###############################################################
#  Generated by:      Cadence Innovus 21.35-s114_1
#  OS:                Linux x86_64(Host ID pc231.ee.hacettepe.edu.tr)
#  Generated on:      Wed Dec 24 15:13:07 2025
#  Design:            adc_subsystem_macro
#  Command:           write_lef_abstract -5.7 outputs/adc_subsystem_macro/adc_subsystem_macro.lef
###############################################################

VERSION 5.7 ;

BUSBITCHARS "[]" ;
DIVIDERCHAR "/" ;

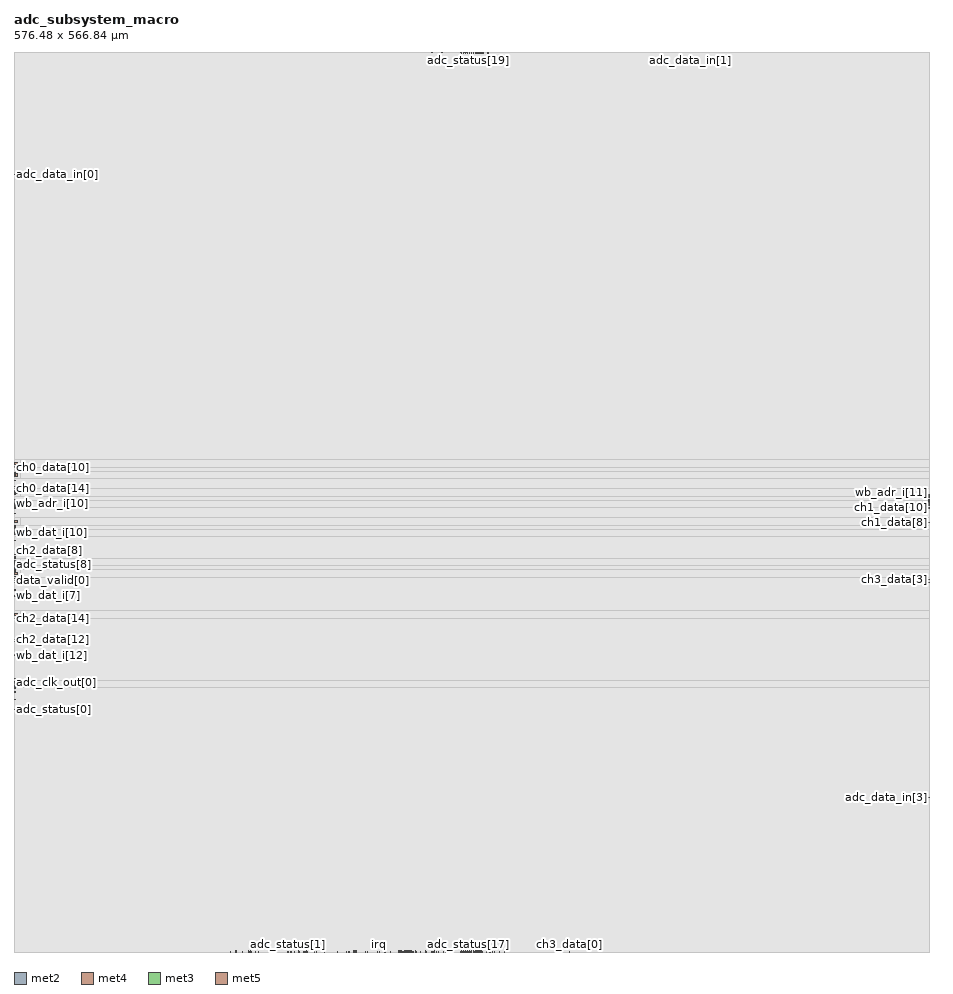
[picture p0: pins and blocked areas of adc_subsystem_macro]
MACRO adc_subsystem_macro
  CLASS BLOCK ;
  SIZE 576.480000 BY 566.840000 ;
  FOREIGN adc_subsystem_macro 0.000000 0.000000 ;
  ORIGIN 0 0 ;
  SYMMETRY X Y R90 ;
  PIN clk
    DIRECTION INPUT ;
    USE SIGNAL ;
    PORT
      LAYER met2 ;
        RECT 276.170000 0.000000 276.310000 0.485000 ;
    END
  END clk
  PIN rst_n
    DIRECTION INPUT ;
    USE SIGNAL ;
    PORT
      LAYER met4 ;
        RECT 275.610000 0.000000 275.910000 0.800000 ;
    END
  END rst_n
  PIN wb_adr_i[31]
    DIRECTION INPUT ;
    USE SIGNAL ;
    PORT
      LAYER met4 ;
        RECT 291.600000 0.000000 291.900000 0.800000 ;
    END
  END wb_adr_i[31]
  PIN wb_adr_i[30]
    DIRECTION INPUT ;
    USE SIGNAL ;
    PORT
      LAYER met2 ;
        RECT 284.330000 566.355000 284.470000 566.840000 ;
    END
  END wb_adr_i[30]
  PIN wb_adr_i[29]
    DIRECTION INPUT ;
    USE SIGNAL ;
    PORT
      LAYER met2 ;
        RECT 292.010000 0.000000 292.150000 0.485000 ;
    END
  END wb_adr_i[29]
  PIN wb_adr_i[28]
    DIRECTION INPUT ;
    USE SIGNAL ;
    PORT
      LAYER met4 ;
        RECT 284.220000 566.040000 284.520000 566.840000 ;
    END
  END wb_adr_i[28]
  PIN wb_adr_i[27]
    DIRECTION INPUT ;
    USE SIGNAL ;
    PORT
      LAYER met2 ;
        RECT 292.970000 566.355000 293.110000 566.840000 ;
    END
  END wb_adr_i[27]
  PIN wb_adr_i[26]
    DIRECTION INPUT ;
    USE SIGNAL ;
    PORT
      LAYER met4 ;
        RECT 292.830000 566.040000 293.130000 566.840000 ;
    END
  END wb_adr_i[26]
  PIN wb_adr_i[25]
    DIRECTION INPUT ;
    USE SIGNAL ;
    PORT
      LAYER met2 ;
        RECT 292.970000 0.000000 293.110000 0.485000 ;
    END
  END wb_adr_i[25]
  PIN wb_adr_i[24]
    DIRECTION INPUT ;
    USE SIGNAL ;
    PORT
      LAYER met4 ;
        RECT 292.830000 0.000000 293.130000 0.800000 ;
    END
  END wb_adr_i[24]
  PIN wb_adr_i[23]
    DIRECTION INPUT ;
    USE SIGNAL ;
    PORT
      LAYER met2 ;
        RECT 283.370000 566.355000 283.510000 566.840000 ;
    END
  END wb_adr_i[23]
  PIN wb_adr_i[22]
    DIRECTION INPUT ;
    USE SIGNAL ;
    PORT
      LAYER met3 ;
        RECT 0.000000 283.260000 0.800000 283.560000 ;
    END
  END wb_adr_i[22]
  PIN wb_adr_i[21]
    DIRECTION INPUT ;
    USE SIGNAL ;
    PORT
      LAYER met3 ;
        RECT 575.680000 283.260000 576.480000 283.560000 ;
    END
  END wb_adr_i[21]
  PIN wb_adr_i[20]
    DIRECTION INPUT ;
    USE SIGNAL ;
    PORT
      LAYER met4 ;
        RECT 282.990000 566.040000 283.290000 566.840000 ;
    END
  END wb_adr_i[20]
  PIN wb_adr_i[19]
    DIRECTION INPUT ;
    USE SIGNAL ;
    PORT
      LAYER met4 ;
        RECT 282.990000 0.000000 283.290000 0.800000 ;
    END
  END wb_adr_i[19]
  PIN wb_adr_i[18]
    DIRECTION INPUT ;
    USE SIGNAL ;
    PORT
      LAYER met2 ;
        RECT 282.410000 566.355000 282.550000 566.840000 ;
    END
  END wb_adr_i[18]
  PIN wb_adr_i[17]
    DIRECTION INPUT ;
    USE SIGNAL ;
    PORT
      LAYER met2 ;
        RECT 293.930000 566.355000 294.070000 566.840000 ;
    END
  END wb_adr_i[17]
  PIN wb_adr_i[16]
    DIRECTION INPUT ;
    USE SIGNAL ;
    PORT
      LAYER met2 ;
        RECT 282.410000 0.000000 282.550000 0.485000 ;
    END
  END wb_adr_i[16]
  PIN wb_adr_i[15]
    DIRECTION INPUT ;
    USE SIGNAL ;
    PORT
      LAYER met2 ;
        RECT 293.930000 0.000000 294.070000 0.485000 ;
    END
  END wb_adr_i[15]
  PIN wb_adr_i[14]
    DIRECTION INPUT ;
    USE SIGNAL ;
    PORT
      LAYER met4 ;
        RECT 294.060000 566.040000 294.360000 566.840000 ;
    END
  END wb_adr_i[14]
  PIN wb_adr_i[13]
    DIRECTION INPUT ;
    USE SIGNAL ;
    PORT
      LAYER met4 ;
        RECT 294.060000 0.000000 294.360000 0.800000 ;
    END
  END wb_adr_i[13]
  PIN wb_adr_i[12]
    DIRECTION INPUT ;
    USE SIGNAL ;
    PORT
      LAYER met3 ;
        RECT 0.000000 284.480000 0.800000 284.780000 ;
    END
  END wb_adr_i[12]
  PIN wb_adr_i[11]
    DIRECTION INPUT ;
    USE SIGNAL ;
    PORT
      LAYER met3 ;
        RECT 575.680000 284.480000 576.480000 284.780000 ;
    END
  END wb_adr_i[11]
  PIN wb_adr_i[10]
    DIRECTION INPUT ;
    USE SIGNAL ;
    PORT
      LAYER met3 ;
        RECT 0.000000 282.040000 0.800000 282.340000 ;
    END
  END wb_adr_i[10]
  PIN wb_adr_i[9]
    DIRECTION INPUT ;
    USE SIGNAL ;
    PORT
      LAYER met5 ;
        RECT 0.000000 281.390000 2.500000 282.990000 ;
    END
  END wb_adr_i[9]
  PIN wb_adr_i[8]
    DIRECTION INPUT ;
    USE SIGNAL ;
    PORT
      LAYER met3 ;
        RECT 575.680000 282.040000 576.480000 282.340000 ;
    END
  END wb_adr_i[8]
  PIN wb_adr_i[7]
    DIRECTION INPUT ;
    USE SIGNAL ;
    PORT
      LAYER met2 ;
        RECT 259.370000 0.000000 259.510000 0.485000 ;
    END
  END wb_adr_i[7]
  PIN wb_adr_i[6]
    DIRECTION INPUT ;
    USE SIGNAL ;
    PORT
      LAYER met4 ;
        RECT 259.005000 0.000000 259.305000 0.800000 ;
    END
  END wb_adr_i[6]
  PIN wb_adr_i[5]
    DIRECTION INPUT ;
    USE SIGNAL ;
    PORT
      LAYER met2 ;
        RECT 233.930000 0.000000 234.070000 0.485000 ;
    END
  END wb_adr_i[5]
  PIN wb_adr_i[4]
    DIRECTION INPUT ;
    USE SIGNAL ;
    PORT
      LAYER met4 ;
        RECT 248.550000 0.000000 248.850000 0.800000 ;
    END
  END wb_adr_i[4]
  PIN wb_adr_i[3]
    DIRECTION INPUT ;
    USE SIGNAL ;
    PORT
      LAYER met2 ;
        RECT 244.010000 0.000000 244.150000 0.485000 ;
    END
  END wb_adr_i[3]
  PIN wb_adr_i[2]
    DIRECTION INPUT ;
    USE SIGNAL ;
    PORT
      LAYER met2 ;
        RECT 248.330000 0.000000 248.470000 0.485000 ;
    END
  END wb_adr_i[2]
  PIN wb_adr_i[1]
    DIRECTION INPUT ;
    USE SIGNAL ;
    PORT
      LAYER met5 ;
        RECT 573.980000 281.390000 576.480000 282.990000 ;
    END
  END wb_adr_i[1]
  PIN wb_adr_i[0]
    DIRECTION INPUT ;
    USE SIGNAL ;
    PORT
      LAYER met4 ;
        RECT 281.760000 566.040000 282.060000 566.840000 ;
    END
  END wb_adr_i[0]
  PIN wb_dat_o[31]
    DIRECTION OUTPUT ;
    USE SIGNAL ;
    PORT
      LAYER met2 ;
        RECT 250.250000 0.000000 250.390000 0.485000 ;
    END
  END wb_dat_o[31]
  PIN wb_dat_o[30]
    DIRECTION OUTPUT ;
    USE SIGNAL ;
    PORT
      LAYER met2 ;
        RECT 242.570000 0.000000 242.710000 0.485000 ;
    END
  END wb_dat_o[30]
  PIN wb_dat_o[29]
    DIRECTION OUTPUT ;
    USE SIGNAL ;
    PORT
      LAYER met2 ;
        RECT 174.410000 0.000000 174.550000 0.485000 ;
    END
  END wb_dat_o[29]
  PIN wb_dat_o[28]
    DIRECTION OUTPUT ;
    USE SIGNAL ;
    PORT
      LAYER met4 ;
        RECT 147.690000 0.000000 147.990000 0.800000 ;
    END
  END wb_dat_o[28]
  PIN wb_dat_o[27]
    DIRECTION OUTPUT ;
    USE SIGNAL ;
    PORT
      LAYER met4 ;
        RECT 246.090000 0.000000 246.390000 0.800000 ;
    END
  END wb_dat_o[27]
  PIN wb_dat_o[26]
    DIRECTION OUTPUT ;
    USE SIGNAL ;
    PORT
      LAYER met4 ;
        RECT 179.055000 0.000000 179.355000 0.800000 ;
    END
  END wb_dat_o[26]
  PIN wb_dat_o[25]
    DIRECTION OUTPUT ;
    USE SIGNAL ;
    PORT
      LAYER met2 ;
        RECT 136.490000 0.000000 136.630000 0.485000 ;
    END
  END wb_dat_o[25]
  PIN wb_dat_o[24]
    DIRECTION OUTPUT ;
    USE SIGNAL ;
    PORT
      LAYER met2 ;
        RECT 183.530000 0.000000 183.670000 0.485000 ;
    END
  END wb_dat_o[24]
  PIN wb_dat_o[23]
    DIRECTION OUTPUT ;
    USE SIGNAL ;
    PORT
      LAYER met2 ;
        RECT 244.970000 0.000000 245.110000 0.485000 ;
    END
  END wb_dat_o[23]
  PIN wb_dat_o[22]
    DIRECTION OUTPUT ;
    USE SIGNAL ;
    PORT
      LAYER met2 ;
        RECT 139.370000 0.000000 139.510000 0.485000 ;
    END
  END wb_dat_o[22]
  PIN wb_dat_o[21]
    DIRECTION OUTPUT ;
    USE SIGNAL ;
    PORT
      LAYER met4 ;
        RECT 247.320000 0.000000 247.620000 0.800000 ;
    END
  END wb_dat_o[21]
  PIN wb_dat_o[20]
    DIRECTION OUTPUT ;
    USE SIGNAL ;
    PORT
      LAYER met2 ;
        RECT 143.690000 0.000000 143.830000 0.485000 ;
    END
  END wb_dat_o[20]
  PIN wb_dat_o[19]
    DIRECTION OUTPUT ;
    USE SIGNAL ;
    PORT
      LAYER met2 ;
        RECT 209.450000 0.000000 209.590000 0.485000 ;
    END
  END wb_dat_o[19]
  PIN wb_dat_o[18]
    DIRECTION OUTPUT ;
    USE SIGNAL ;
    PORT
      LAYER met4 ;
        RECT 214.110000 0.000000 214.410000 0.800000 ;
    END
  END wb_dat_o[18]
  PIN wb_dat_o[17]
    DIRECTION OUTPUT ;
    USE SIGNAL ;
    PORT
      LAYER met2 ;
        RECT 182.570000 0.000000 182.710000 0.485000 ;
    END
  END wb_dat_o[17]
  PIN wb_dat_o[16]
    DIRECTION OUTPUT ;
    USE SIGNAL ;
    PORT
      LAYER met4 ;
        RECT 139.695000 0.000000 139.995000 0.800000 ;
    END
  END wb_dat_o[16]
  PIN wb_dat_o[15]
    DIRECTION OUTPUT ;
    USE SIGNAL ;
    PORT
      LAYER met3 ;
        RECT 0.000000 163.700000 0.800000 164.000000 ;
    END
  END wb_dat_o[15]
  PIN wb_dat_o[14]
    DIRECTION OUTPUT ;
    USE SIGNAL ;
    PORT
      LAYER met5 ;
        RECT 0.000000 211.850000 2.500000 213.450000 ;
    END
  END wb_dat_o[14]
  PIN wb_dat_o[13]
    DIRECTION OUTPUT ;
    USE SIGNAL ;
    PORT
      LAYER met5 ;
        RECT 0.000000 167.930000 2.500000 169.530000 ;
    END
  END wb_dat_o[13]
  PIN wb_dat_o[12]
    DIRECTION OUTPUT ;
    USE SIGNAL ;
    PORT
      LAYER met3 ;
        RECT 0.000000 195.420000 0.800000 195.720000 ;
    END
  END wb_dat_o[12]
  PIN wb_dat_o[11]
    DIRECTION OUTPUT ;
    USE SIGNAL ;
    PORT
      LAYER met3 ;
        RECT 0.000000 233.850000 0.800000 234.150000 ;
    END
  END wb_dat_o[11]
  PIN wb_dat_o[10]
    DIRECTION OUTPUT ;
    USE SIGNAL ;
    PORT
      LAYER met3 ;
        RECT 0.000000 249.100000 0.800000 249.400000 ;
    END
  END wb_dat_o[10]
  PIN wb_dat_o[9]
    DIRECTION OUTPUT ;
    USE SIGNAL ;
    PORT
      LAYER met3 ;
        RECT 0.000000 268.010000 0.800000 268.310000 ;
    END
  END wb_dat_o[9]
  PIN wb_dat_o[8]
    DIRECTION OUTPUT ;
    USE SIGNAL ;
    PORT
      LAYER met3 ;
        RECT 0.000000 250.320000 0.800000 250.620000 ;
    END
  END wb_dat_o[8]
  PIN wb_dat_o[7]
    DIRECTION OUTPUT ;
    USE SIGNAL ;
    PORT
      LAYER met3 ;
        RECT 0.000000 232.630000 0.800000 232.930000 ;
    END
  END wb_dat_o[7]
  PIN wb_dat_o[6]
    DIRECTION OUTPUT ;
    USE SIGNAL ;
    PORT
      LAYER met3 ;
        RECT 0.000000 275.940000 0.800000 276.240000 ;
    END
  END wb_dat_o[6]
  PIN wb_dat_o[5]
    DIRECTION OUTPUT ;
    USE SIGNAL ;
    PORT
      LAYER met3 ;
        RECT 0.000000 279.600000 0.800000 279.900000 ;
    END
  END wb_dat_o[5]
  PIN wb_dat_o[4]
    DIRECTION OUTPUT ;
    USE SIGNAL ;
    PORT
      LAYER met3 ;
        RECT 0.000000 280.820000 0.800000 281.120000 ;
    END
  END wb_dat_o[4]
  PIN wb_dat_o[3]
    DIRECTION OUTPUT ;
    USE SIGNAL ;
    PORT
      LAYER met2 ;
        RECT 221.450000 0.000000 221.590000 0.485000 ;
    END
  END wb_dat_o[3]
  PIN wb_dat_o[2]
    DIRECTION OUTPUT ;
    USE SIGNAL ;
    PORT
      LAYER met4 ;
        RECT 242.400000 0.000000 242.700000 0.800000 ;
    END
  END wb_dat_o[2]
  PIN wb_dat_o[1]
    DIRECTION OUTPUT ;
    USE SIGNAL ;
    PORT
      LAYER met2 ;
        RECT 251.210000 0.000000 251.350000 0.485000 ;
    END
  END wb_dat_o[1]
  PIN wb_dat_o[0]
    DIRECTION OUTPUT ;
    USE SIGNAL ;
    PORT
      LAYER met2 ;
        RECT 222.410000 0.000000 222.550000 0.485000 ;
    END
  END wb_dat_o[0]
  PIN wb_dat_i[31]
    DIRECTION INPUT ;
    USE SIGNAL ;
    PORT
      LAYER met4 ;
        RECT 249.780000 0.000000 250.080000 0.800000 ;
    END
  END wb_dat_i[31]
  PIN wb_dat_i[30]
    DIRECTION INPUT ;
    USE SIGNAL ;
    PORT
      LAYER met4 ;
        RECT 233.175000 0.000000 233.475000 0.800000 ;
    END
  END wb_dat_i[30]
  PIN wb_dat_i[29]
    DIRECTION INPUT ;
    USE SIGNAL ;
    PORT
      LAYER met2 ;
        RECT 184.490000 0.000000 184.630000 0.485000 ;
    END
  END wb_dat_i[29]
  PIN wb_dat_i[28]
    DIRECTION INPUT ;
    USE SIGNAL ;
    PORT
      LAYER met2 ;
        RECT 148.490000 0.000000 148.630000 0.485000 ;
    END
  END wb_dat_i[28]
  PIN wb_dat_i[27]
    DIRECTION INPUT ;
    USE SIGNAL ;
    PORT
      LAYER met2 ;
        RECT 228.650000 0.000000 228.790000 0.485000 ;
    END
  END wb_dat_i[27]
  PIN wb_dat_i[26]
    DIRECTION INPUT ;
    USE SIGNAL ;
    PORT
      LAYER met4 ;
        RECT 183.975000 0.000000 184.275000 0.800000 ;
    END
  END wb_dat_i[26]
  PIN wb_dat_i[25]
    DIRECTION INPUT ;
    USE SIGNAL ;
    PORT
      LAYER met2 ;
        RECT 151.850000 0.000000 151.990000 0.485000 ;
    END
  END wb_dat_i[25]
  PIN wb_dat_i[24]
    DIRECTION INPUT ;
    USE SIGNAL ;
    PORT
      LAYER met2 ;
        RECT 189.290000 0.000000 189.430000 0.485000 ;
    END
  END wb_dat_i[24]
  PIN wb_dat_i[23]
    DIRECTION INPUT ;
    USE SIGNAL ;
    PORT
      LAYER met4 ;
        RECT 243.630000 0.000000 243.930000 0.800000 ;
    END
  END wb_dat_i[23]
  PIN wb_dat_i[22]
    DIRECTION INPUT ;
    USE SIGNAL ;
    PORT
      LAYER met4 ;
        RECT 148.920000 0.000000 149.220000 0.800000 ;
    END
  END wb_dat_i[22]
  PIN wb_dat_i[21]
    DIRECTION INPUT ;
    USE SIGNAL ;
    PORT
      LAYER met2 ;
        RECT 247.370000 0.000000 247.510000 0.485000 ;
    END
  END wb_dat_i[21]
  PIN wb_dat_i[20]
    DIRECTION INPUT ;
    USE SIGNAL ;
    PORT
      LAYER met2 ;
        RECT 153.770000 0.000000 153.910000 0.485000 ;
    END
  END wb_dat_i[20]
  PIN wb_dat_i[19]
    DIRECTION INPUT ;
    USE SIGNAL ;
    PORT
      LAYER met2 ;
        RECT 214.730000 0.000000 214.870000 0.485000 ;
    END
  END wb_dat_i[19]
  PIN wb_dat_i[18]
    DIRECTION INPUT ;
    USE SIGNAL ;
    PORT
      LAYER met2 ;
        RECT 210.890000 0.000000 211.030000 0.485000 ;
    END
  END wb_dat_i[18]
  PIN wb_dat_i[17]
    DIRECTION INPUT ;
    USE SIGNAL ;
    PORT
      LAYER met2 ;
        RECT 190.250000 0.000000 190.390000 0.485000 ;
    END
  END wb_dat_i[17]
  PIN wb_dat_i[16]
    DIRECTION INPUT ;
    USE SIGNAL ;
    PORT
      LAYER met2 ;
        RECT 149.450000 0.000000 149.590000 0.485000 ;
    END
  END wb_dat_i[16]
  PIN wb_dat_i[15]
    DIRECTION INPUT ;
    USE SIGNAL ;
    PORT
      LAYER met2 ;
        RECT 179.690000 0.000000 179.830000 0.485000 ;
    END
  END wb_dat_i[15]
  PIN wb_dat_i[14]
    DIRECTION INPUT ;
    USE SIGNAL ;
    PORT
      LAYER met3 ;
        RECT 0.000000 211.890000 0.800000 212.190000 ;
    END
  END wb_dat_i[14]
  PIN wb_dat_i[13]
    DIRECTION INPUT ;
    USE SIGNAL ;
    PORT
      LAYER met2 ;
        RECT 176.810000 0.000000 176.950000 0.485000 ;
    END
  END wb_dat_i[13]
  PIN wb_dat_i[12]
    DIRECTION INPUT ;
    USE SIGNAL ;
    PORT
      LAYER met3 ;
        RECT 0.000000 186.880000 0.800000 187.180000 ;
    END
  END wb_dat_i[12]
  PIN wb_dat_i[11]
    DIRECTION INPUT ;
    USE SIGNAL ;
    PORT
      LAYER met3 ;
        RECT 0.000000 246.050000 0.800000 246.350000 ;
    END
  END wb_dat_i[11]
  PIN wb_dat_i[10]
    DIRECTION INPUT ;
    USE SIGNAL ;
    PORT
      LAYER met3 ;
        RECT 0.000000 264.350000 0.800000 264.650000 ;
    END
  END wb_dat_i[10]
  PIN wb_dat_i[9]
    DIRECTION INPUT ;
    USE SIGNAL ;
    PORT
      LAYER met3 ;
        RECT 0.000000 270.450000 0.800000 270.750000 ;
    END
  END wb_dat_i[9]
  PIN wb_dat_i[8]
    DIRECTION INPUT ;
    USE SIGNAL ;
    PORT
      LAYER met3 ;
        RECT 0.000000 258.860000 0.800000 259.160000 ;
    END
  END wb_dat_i[8]
  PIN wb_dat_i[7]
    DIRECTION INPUT ;
    USE SIGNAL ;
    PORT
      LAYER met3 ;
        RECT 0.000000 224.090000 0.800000 224.390000 ;
    END
  END wb_dat_i[7]
  PIN wb_dat_i[6]
    DIRECTION INPUT ;
    USE SIGNAL ;
    PORT
      LAYER met3 ;
        RECT 0.000000 266.790000 0.800000 267.090000 ;
    END
  END wb_dat_i[6]
  PIN wb_dat_i[5]
    DIRECTION INPUT ;
    USE SIGNAL ;
    PORT
      LAYER met5 ;
        RECT 0.000000 270.410000 2.500000 272.010000 ;
    END
  END wb_dat_i[5]
  PIN wb_dat_i[4]
    DIRECTION INPUT ;
    USE SIGNAL ;
    PORT
      LAYER met3 ;
        RECT 0.000000 265.570000 0.800000 265.870000 ;
    END
  END wb_dat_i[4]
  PIN wb_dat_i[3]
    DIRECTION INPUT ;
    USE SIGNAL ;
    PORT
      LAYER met2 ;
        RECT 203.690000 0.000000 203.830000 0.485000 ;
    END
  END wb_dat_i[3]
  PIN wb_dat_i[2]
    DIRECTION INPUT ;
    USE SIGNAL ;
    PORT
      LAYER met4 ;
        RECT 215.340000 0.000000 215.640000 0.800000 ;
    END
  END wb_dat_i[2]
  PIN wb_dat_i[1]
    DIRECTION INPUT ;
    USE SIGNAL ;
    PORT
      LAYER met2 ;
        RECT 237.290000 0.000000 237.430000 0.485000 ;
    END
  END wb_dat_i[1]
  PIN wb_dat_i[0]
    DIRECTION INPUT ;
    USE SIGNAL ;
    PORT
      LAYER met2 ;
        RECT 195.530000 0.000000 195.670000 0.485000 ;
    END
  END wb_dat_i[0]
  PIN wb_we_i
    DIRECTION INPUT ;
    USE SIGNAL ;
    PORT
      LAYER met2 ;
        RECT 253.610000 0.000000 253.750000 0.485000 ;
    END
  END wb_we_i
  PIN wb_sel_i[3]
    DIRECTION INPUT ;
    USE SIGNAL ;
    PORT
      LAYER met4 ;
        RECT 281.760000 0.000000 282.060000 0.800000 ;
    END
  END wb_sel_i[3]
  PIN wb_sel_i[2]
    DIRECTION INPUT ;
    USE SIGNAL ;
    PORT
      LAYER met2 ;
        RECT 281.450000 566.355000 281.590000 566.840000 ;
    END
  END wb_sel_i[2]
  PIN wb_sel_i[1]
    DIRECTION INPUT ;
    USE SIGNAL ;
    PORT
      LAYER met2 ;
        RECT 281.450000 0.000000 281.590000 0.485000 ;
    END
  END wb_sel_i[1]
  PIN wb_sel_i[0]
    DIRECTION INPUT ;
    USE SIGNAL ;
    PORT
      LAYER met2 ;
        RECT 294.890000 0.000000 295.030000 0.485000 ;
    END
  END wb_sel_i[0]
  PIN wb_cyc_i
    DIRECTION INPUT ;
    USE SIGNAL ;
    PORT
      LAYER met4 ;
        RECT 264.540000 0.000000 264.840000 0.800000 ;
    END
  END wb_cyc_i
  PIN wb_stb_i
    DIRECTION INPUT ;
    USE SIGNAL ;
    PORT
      LAYER met2 ;
        RECT 263.210000 0.000000 263.350000 0.485000 ;
    END
  END wb_stb_i
  PIN wb_ack_o
    DIRECTION OUTPUT ;
    USE SIGNAL ;
    PORT
      LAYER met2 ;
        RECT 266.090000 0.000000 266.230000 0.485000 ;
    END
  END wb_ack_o
  PIN wb_err_o
    DIRECTION OUTPUT ;
    USE SIGNAL ;
    PORT
      LAYER met4 ;
        RECT 295.290000 566.040000 295.590000 566.840000 ;
    END
  END wb_err_o
  PIN adc_data_in[3]
    DIRECTION INPUT ;
    USE SIGNAL ;
    PORT
      LAYER met3 ;
        RECT 575.680000 97.210000 576.480000 97.510000 ;
    END
  END adc_data_in[3]
  PIN adc_data_in[2]
    DIRECTION INPUT ;
    USE SIGNAL ;
    PORT
      LAYER met3 ;
        RECT 575.680000 286.310000 576.480000 286.610000 ;
    END
  END adc_data_in[2]
  PIN adc_data_in[1]
    DIRECTION INPUT ;
    USE SIGNAL ;
    PORT
      LAYER met2 ;
        RECT 425.930000 566.355000 426.070000 566.840000 ;
    END
  END adc_data_in[1]
  PIN adc_data_in[0]
    DIRECTION INPUT ;
    USE SIGNAL ;
    PORT
      LAYER met3 ;
        RECT 0.000000 489.440000 0.800000 489.740000 ;
    END
  END adc_data_in[0]
  PIN adc_clk_out[3]
    DIRECTION OUTPUT ;
    USE SIGNAL ;
    PORT
      LAYER met3 ;
        RECT 0.000000 166.140000 0.800000 166.440000 ;
    END
  END adc_clk_out[3]
  PIN adc_clk_out[2]
    DIRECTION OUTPUT ;
    USE SIGNAL ;
    PORT
      LAYER met3 ;
        RECT 0.000000 167.360000 0.800000 167.660000 ;
    END
  END adc_clk_out[2]
  PIN adc_clk_out[1]
    DIRECTION OUTPUT ;
    USE SIGNAL ;
    PORT
      LAYER met3 ;
        RECT 0.000000 168.580000 0.800000 168.880000 ;
    END
  END adc_clk_out[1]
  PIN adc_clk_out[0]
    DIRECTION OUTPUT ;
    USE SIGNAL ;
    PORT
      LAYER met3 ;
        RECT 0.000000 169.800000 0.800000 170.100000 ;
    END
  END adc_clk_out[0]
  PIN ch0_data[15]
    DIRECTION OUTPUT ;
    USE SIGNAL ;
    PORT
      LAYER met2 ;
        RECT 272.810000 566.355000 272.950000 566.840000 ;
    END
  END ch0_data[15]
  PIN ch0_data[14]
    DIRECTION OUTPUT ;
    USE SIGNAL ;
    PORT
      LAYER met3 ;
        RECT 0.000000 296.680000 0.800000 296.980000 ;
    END
  END ch0_data[14]
  PIN ch0_data[13]
    DIRECTION OUTPUT ;
    USE SIGNAL ;
    PORT
      LAYER met2 ;
        RECT 266.090000 566.355000 266.230000 566.840000 ;
    END
  END ch0_data[13]
  PIN ch0_data[12]
    DIRECTION OUTPUT ;
    USE SIGNAL ;
    PORT
      LAYER met2 ;
        RECT 251.690000 566.355000 251.830000 566.840000 ;
    END
  END ch0_data[12]
  PIN ch0_data[11]
    DIRECTION OUTPUT ;
    USE SIGNAL ;
    PORT
      LAYER met3 ;
        RECT 0.000000 301.560000 0.800000 301.860000 ;
    END
  END ch0_data[11]
  PIN ch0_data[10]
    DIRECTION OUTPUT ;
    USE SIGNAL ;
    PORT
      LAYER met3 ;
        RECT 0.000000 305.220000 0.800000 305.520000 ;
    END
  END ch0_data[10]
  PIN ch0_data[9]
    DIRECTION OUTPUT ;
    USE SIGNAL ;
    PORT
      LAYER met3 ;
        RECT 0.000000 307.050000 0.800000 307.350000 ;
    END
  END ch0_data[9]
  PIN ch0_data[8]
    DIRECTION OUTPUT ;
    USE SIGNAL ;
    PORT
      LAYER met3 ;
        RECT 0.000000 300.340000 0.800000 300.640000 ;
    END
  END ch0_data[8]
  PIN ch0_data[7]
    DIRECTION OUTPUT ;
    USE SIGNAL ;
    PORT
      LAYER met2 ;
        RECT 248.330000 566.355000 248.470000 566.840000 ;
    END
  END ch0_data[7]
  PIN ch0_data[6]
    DIRECTION OUTPUT ;
    USE SIGNAL ;
    PORT
      LAYER met5 ;
        RECT 0.000000 299.690000 2.500000 301.290000 ;
    END
  END ch0_data[6]
  PIN ch0_data[5]
    DIRECTION OUTPUT ;
    USE SIGNAL ;
    PORT
      LAYER met5 ;
        RECT 0.000000 307.010000 2.500000 308.610000 ;
    END
  END ch0_data[5]
  PIN ch0_data[4]
    DIRECTION OUTPUT ;
    USE SIGNAL ;
    PORT
      LAYER met3 ;
        RECT 0.000000 308.270000 0.800000 308.570000 ;
    END
  END ch0_data[4]
  PIN ch0_data[3]
    DIRECTION OUTPUT ;
    USE SIGNAL ;
    PORT
      LAYER met3 ;
        RECT 0.000000 288.140000 0.800000 288.440000 ;
    END
  END ch0_data[3]
  PIN ch0_data[2]
    DIRECTION OUTPUT ;
    USE SIGNAL ;
    PORT
      LAYER met2 ;
        RECT 245.930000 566.355000 246.070000 566.840000 ;
    END
  END ch0_data[2]
  PIN ch0_data[1]
    DIRECTION OUTPUT ;
    USE SIGNAL ;
    PORT
      LAYER met3 ;
        RECT 0.000000 289.360000 0.800000 289.660000 ;
    END
  END ch0_data[1]
  PIN ch0_data[0]
    DIRECTION OUTPUT ;
    USE SIGNAL ;
    PORT
      LAYER met5 ;
        RECT 0.000000 288.710000 2.500000 290.310000 ;
    END
  END ch0_data[0]
  PIN ch1_data[15]
    DIRECTION OUTPUT ;
    USE SIGNAL ;
    PORT
      LAYER met2 ;
        RECT 268.490000 566.355000 268.630000 566.840000 ;
    END
  END ch1_data[15]
  PIN ch1_data[14]
    DIRECTION OUTPUT ;
    USE SIGNAL ;
    PORT
      LAYER met2 ;
        RECT 270.410000 0.000000 270.550000 0.485000 ;
    END
  END ch1_data[14]
  PIN ch1_data[13]
    DIRECTION OUTPUT ;
    USE SIGNAL ;
    PORT
      LAYER met2 ;
        RECT 259.850000 566.355000 259.990000 566.840000 ;
    END
  END ch1_data[13]
  PIN ch1_data[12]
    DIRECTION OUTPUT ;
    USE SIGNAL ;
    PORT
      LAYER met2 ;
        RECT 267.050000 566.355000 267.190000 566.840000 ;
    END
  END ch1_data[12]
  PIN ch1_data[11]
    DIRECTION OUTPUT ;
    USE SIGNAL ;
    PORT
      LAYER met2 ;
        RECT 284.330000 0.000000 284.470000 0.485000 ;
    END
  END ch1_data[11]
  PIN ch1_data[10]
    DIRECTION OUTPUT ;
    USE SIGNAL ;
    PORT
      LAYER met3 ;
        RECT 575.680000 279.600000 576.480000 279.900000 ;
    END
  END ch1_data[10]
  PIN ch1_data[9]
    DIRECTION OUTPUT ;
    USE SIGNAL ;
    PORT
      LAYER met3 ;
        RECT 575.680000 287.530000 576.480000 287.830000 ;
    END
  END ch1_data[9]
  PIN ch1_data[8]
    DIRECTION OUTPUT ;
    USE SIGNAL ;
    PORT
      LAYER met3 ;
        RECT 575.680000 270.450000 576.480000 270.750000 ;
    END
  END ch1_data[8]
  PIN ch1_data[7]
    DIRECTION OUTPUT ;
    USE SIGNAL ;
    PORT
      LAYER met2 ;
        RECT 263.210000 566.355000 263.350000 566.840000 ;
    END
  END ch1_data[7]
  PIN ch1_data[6]
    DIRECTION OUTPUT ;
    USE SIGNAL ;
    PORT
      LAYER met2 ;
        RECT 298.730000 566.355000 298.870000 566.840000 ;
    END
  END ch1_data[6]
  PIN ch1_data[5]
    DIRECTION OUTPUT ;
    USE SIGNAL ;
    PORT
      LAYER met2 ;
        RECT 301.130000 566.355000 301.270000 566.840000 ;
    END
  END ch1_data[5]
  PIN ch1_data[4]
    DIRECTION OUTPUT ;
    USE SIGNAL ;
    PORT
      LAYER met2 ;
        RECT 294.890000 566.355000 295.030000 566.840000 ;
    END
  END ch1_data[4]
  PIN ch1_data[3]
    DIRECTION OUTPUT ;
    USE SIGNAL ;
    PORT
      LAYER met4 ;
        RECT 291.600000 566.040000 291.900000 566.840000 ;
    END
  END ch1_data[3]
  PIN ch1_data[2]
    DIRECTION OUTPUT ;
    USE SIGNAL ;
    PORT
      LAYER met2 ;
        RECT 269.450000 566.355000 269.590000 566.840000 ;
    END
  END ch1_data[2]
  PIN ch1_data[1]
    DIRECTION OUTPUT ;
    USE SIGNAL ;
    PORT
      LAYER met2 ;
        RECT 292.010000 566.355000 292.150000 566.840000 ;
    END
  END ch1_data[1]
  PIN ch1_data[0]
    DIRECTION OUTPUT ;
    USE SIGNAL ;
    PORT
      LAYER met4 ;
        RECT 298.365000 566.040000 298.665000 566.840000 ;
    END
  END ch1_data[0]
  PIN ch2_data[15]
    DIRECTION OUTPUT ;
    USE SIGNAL ;
    PORT
      LAYER met3 ;
        RECT 0.000000 158.820000 0.800000 159.120000 ;
    END
  END ch2_data[15]
  PIN ch2_data[14]
    DIRECTION OUTPUT ;
    USE SIGNAL ;
    PORT
      LAYER met3 ;
        RECT 0.000000 210.060000 0.800000 210.360000 ;
    END
  END ch2_data[14]
  PIN ch2_data[13]
    DIRECTION OUTPUT ;
    USE SIGNAL ;
    PORT
      LAYER met3 ;
        RECT 0.000000 172.240000 0.800000 172.540000 ;
    END
  END ch2_data[13]
  PIN ch2_data[12]
    DIRECTION OUTPUT ;
    USE SIGNAL ;
    PORT
      LAYER met3 ;
        RECT 0.000000 196.640000 0.800000 196.940000 ;
    END
  END ch2_data[12]
  PIN ch2_data[11]
    DIRECTION OUTPUT ;
    USE SIGNAL ;
    PORT
      LAYER met3 ;
        RECT 0.000000 227.750000 0.800000 228.050000 ;
    END
  END ch2_data[11]
  PIN ch2_data[10]
    DIRECTION OUTPUT ;
    USE SIGNAL ;
    PORT
      LAYER met3 ;
        RECT 0.000000 244.830000 0.800000 245.130000 ;
    END
  END ch2_data[10]
  PIN ch2_data[9]
    DIRECTION OUTPUT ;
    USE SIGNAL ;
    PORT
      LAYER met5 ;
        RECT 0.000000 263.090000 2.500000 264.690000 ;
    END
  END ch2_data[9]
  PIN ch2_data[8]
    DIRECTION OUTPUT ;
    USE SIGNAL ;
    PORT
      LAYER met3 ;
        RECT 0.000000 247.880000 0.800000 248.180000 ;
    END
  END ch2_data[8]
  PIN ch2_data[7]
    DIRECTION OUTPUT ;
    USE SIGNAL ;
    PORT
      LAYER met5 ;
        RECT 0.000000 244.790000 2.500000 246.390000 ;
    END
  END ch2_data[7]
  PIN ch2_data[6]
    DIRECTION OUTPUT ;
    USE SIGNAL ;
    PORT
      LAYER met3 ;
        RECT 0.000000 290.580000 0.800000 290.880000 ;
    END
  END ch2_data[6]
  PIN ch2_data[5]
    DIRECTION OUTPUT ;
    USE SIGNAL ;
    PORT
      LAYER met3 ;
        RECT 0.000000 291.800000 0.800000 292.100000 ;
    END
  END ch2_data[5]
  PIN ch2_data[4]
    DIRECTION OUTPUT ;
    USE SIGNAL ;
    PORT
      LAYER met3 ;
        RECT 0.000000 293.020000 0.800000 293.320000 ;
    END
  END ch2_data[4]
  PIN ch2_data[3]
    DIRECTION OUTPUT ;
    USE SIGNAL ;
    PORT
      LAYER met2 ;
        RECT 245.930000 0.000000 246.070000 0.485000 ;
    END
  END ch2_data[3]
  PIN ch2_data[2]
    DIRECTION OUTPUT ;
    USE SIGNAL ;
    PORT
      LAYER met2 ;
        RECT 252.650000 0.000000 252.790000 0.485000 ;
    END
  END ch2_data[2]
  PIN ch2_data[1]
    DIRECTION OUTPUT ;
    USE SIGNAL ;
    PORT
      LAYER met2 ;
        RECT 264.170000 0.000000 264.310000 0.485000 ;
    END
  END ch2_data[1]
  PIN ch2_data[0]
    DIRECTION OUTPUT ;
    USE SIGNAL ;
    PORT
      LAYER met4 ;
        RECT 252.855000 0.000000 253.155000 0.800000 ;
    END
  END ch2_data[0]
  PIN ch3_data[15]
    DIRECTION OUTPUT ;
    USE SIGNAL ;
    PORT
      LAYER met2 ;
        RECT 249.290000 0.000000 249.430000 0.485000 ;
    END
  END ch3_data[15]
  PIN ch3_data[14]
    DIRECTION OUTPUT ;
    USE SIGNAL ;
    PORT
      LAYER met2 ;
        RECT 271.850000 0.000000 271.990000 0.485000 ;
    END
  END ch3_data[14]
  PIN ch3_data[13]
    DIRECTION OUTPUT ;
    USE SIGNAL ;
    PORT
      LAYER met2 ;
        RECT 256.010000 0.000000 256.150000 0.485000 ;
    END
  END ch3_data[13]
  PIN ch3_data[12]
    DIRECTION OUTPUT ;
    USE SIGNAL ;
    PORT
      LAYER met2 ;
        RECT 267.530000 0.000000 267.670000 0.485000 ;
    END
  END ch3_data[12]
  PIN ch3_data[11]
    DIRECTION OUTPUT ;
    USE SIGNAL ;
    PORT
      LAYER met4 ;
        RECT 284.220000 0.000000 284.520000 0.800000 ;
    END
  END ch3_data[11]
  PIN ch3_data[10]
    DIRECTION OUTPUT ;
    USE SIGNAL ;
    PORT
      LAYER met2 ;
        RECT 302.570000 0.000000 302.710000 0.485000 ;
    END
  END ch3_data[10]
  PIN ch3_data[9]
    DIRECTION OUTPUT ;
    USE SIGNAL ;
    PORT
      LAYER met2 ;
        RECT 301.130000 0.000000 301.270000 0.485000 ;
    END
  END ch3_data[9]
  PIN ch3_data[8]
    DIRECTION OUTPUT ;
    USE SIGNAL ;
    PORT
      LAYER met2 ;
        RECT 297.290000 0.000000 297.430000 0.485000 ;
    END
  END ch3_data[8]
  PIN ch3_data[7]
    DIRECTION OUTPUT ;
    USE SIGNAL ;
    PORT
      LAYER met2 ;
        RECT 274.250000 0.000000 274.390000 0.485000 ;
    END
  END ch3_data[7]
  PIN ch3_data[6]
    DIRECTION OUTPUT ;
    USE SIGNAL ;
    PORT
      LAYER met2 ;
        RECT 305.930000 0.000000 306.070000 0.485000 ;
    END
  END ch3_data[6]
  PIN ch3_data[5]
    DIRECTION OUTPUT ;
    USE SIGNAL ;
    PORT
      LAYER met2 ;
        RECT 308.810000 0.000000 308.950000 0.485000 ;
    END
  END ch3_data[5]
  PIN ch3_data[4]
    DIRECTION OUTPUT ;
    USE SIGNAL ;
    PORT
      LAYER met2 ;
        RECT 299.690000 0.000000 299.830000 0.485000 ;
    END
  END ch3_data[4]
  PIN ch3_data[3]
    DIRECTION OUTPUT ;
    USE SIGNAL ;
    PORT
      LAYER met3 ;
        RECT 575.680000 234.460000 576.480000 234.760000 ;
    END
  END ch3_data[3]
  PIN ch3_data[2]
    DIRECTION OUTPUT ;
    USE SIGNAL ;
    PORT
      LAYER met2 ;
        RECT 283.370000 0.000000 283.510000 0.485000 ;
    END
  END ch3_data[2]
  PIN ch3_data[1]
    DIRECTION OUTPUT ;
    USE SIGNAL ;
    PORT
      LAYER met3 ;
        RECT 575.680000 232.630000 576.480000 232.930000 ;
    END
  END ch3_data[1]
  PIN ch3_data[0]
    DIRECTION OUTPUT ;
    USE SIGNAL ;
    PORT
      LAYER met2 ;
        RECT 349.610000 0.000000 349.750000 0.485000 ;
    END
  END ch3_data[0]
  PIN data_valid[3]
    DIRECTION OUTPUT ;
    USE SIGNAL ;
    PORT
      LAYER met3 ;
        RECT 0.000000 235.070000 0.800000 235.370000 ;
    END
  END data_valid[3]
  PIN data_valid[2]
    DIRECTION OUTPUT ;
    USE SIGNAL ;
    PORT
      LAYER met3 ;
        RECT 0.000000 236.290000 0.800000 236.590000 ;
    END
  END data_valid[2]
  PIN data_valid[1]
    DIRECTION OUTPUT ;
    USE SIGNAL ;
    PORT
      LAYER met3 ;
        RECT 0.000000 237.510000 0.800000 237.810000 ;
    END
  END data_valid[1]
  PIN data_valid[0]
    DIRECTION OUTPUT ;
    USE SIGNAL ;
    PORT
      LAYER met3 ;
        RECT 0.000000 238.730000 0.800000 239.030000 ;
    END
  END data_valid[0]
  PIN irq
    DIRECTION OUTPUT ;
    USE SIGNAL ;
    PORT
      LAYER met2 ;
        RECT 230.090000 0.000000 230.230000 0.485000 ;
    END
  END irq
  PIN adc_status[31]
    DIRECTION OUTPUT ;
    USE SIGNAL ;
    PORT
      LAYER met2 ;
        RECT 288.170000 566.355000 288.310000 566.840000 ;
    END
  END adc_status[31]
  PIN adc_status[30]
    DIRECTION OUTPUT ;
    USE SIGNAL ;
    PORT
      LAYER met2 ;
        RECT 288.170000 0.000000 288.310000 0.485000 ;
    END
  END adc_status[30]
  PIN adc_status[29]
    DIRECTION OUTPUT ;
    USE SIGNAL ;
    PORT
      LAYER met4 ;
        RECT 287.910000 566.040000 288.210000 566.840000 ;
    END
  END adc_status[29]
  PIN adc_status[28]
    DIRECTION OUTPUT ;
    USE SIGNAL ;
    PORT
      LAYER met4 ;
        RECT 287.910000 0.000000 288.210000 0.800000 ;
    END
  END adc_status[28]
  PIN adc_status[27]
    DIRECTION OUTPUT ;
    USE SIGNAL ;
    PORT
      LAYER met2 ;
        RECT 287.210000 566.355000 287.350000 566.840000 ;
    END
  END adc_status[27]
  PIN adc_status[26]
    DIRECTION OUTPUT ;
    USE SIGNAL ;
    PORT
      LAYER met2 ;
        RECT 289.130000 566.355000 289.270000 566.840000 ;
    END
  END adc_status[26]
  PIN adc_status[25]
    DIRECTION OUTPUT ;
    USE SIGNAL ;
    PORT
      LAYER met2 ;
        RECT 287.210000 0.000000 287.350000 0.485000 ;
    END
  END adc_status[25]
  PIN adc_status[24]
    DIRECTION OUTPUT ;
    USE SIGNAL ;
    PORT
      LAYER met2 ;
        RECT 289.130000 0.000000 289.270000 0.485000 ;
    END
  END adc_status[24]
  PIN adc_status[23]
    DIRECTION OUTPUT ;
    USE SIGNAL ;
    PORT
      LAYER met4 ;
        RECT 289.140000 566.040000 289.440000 566.840000 ;
    END
  END adc_status[23]
  PIN adc_status[22]
    DIRECTION OUTPUT ;
    USE SIGNAL ;
    PORT
      LAYER met4 ;
        RECT 289.140000 0.000000 289.440000 0.800000 ;
    END
  END adc_status[22]
  PIN adc_status[21]
    DIRECTION OUTPUT ;
    USE SIGNAL ;
    PORT
      LAYER met4 ;
        RECT 286.680000 566.040000 286.980000 566.840000 ;
    END
  END adc_status[21]
  PIN adc_status[20]
    DIRECTION OUTPUT ;
    USE SIGNAL ;
    PORT
      LAYER met4 ;
        RECT 286.680000 0.000000 286.980000 0.800000 ;
    END
  END adc_status[20]
  PIN adc_status[19]
    DIRECTION OUTPUT ;
    USE SIGNAL ;
    PORT
      LAYER met2 ;
        RECT 286.250000 566.355000 286.390000 566.840000 ;
    END
  END adc_status[19]
  PIN adc_status[18]
    DIRECTION OUTPUT ;
    USE SIGNAL ;
    PORT
      LAYER met2 ;
        RECT 290.090000 566.355000 290.230000 566.840000 ;
    END
  END adc_status[18]
  PIN adc_status[17]
    DIRECTION OUTPUT ;
    USE SIGNAL ;
    PORT
      LAYER met2 ;
        RECT 286.250000 0.000000 286.390000 0.485000 ;
    END
  END adc_status[17]
  PIN adc_status[16]
    DIRECTION OUTPUT ;
    USE SIGNAL ;
    PORT
      LAYER met2 ;
        RECT 290.090000 0.000000 290.230000 0.485000 ;
    END
  END adc_status[16]
  PIN adc_status[15]
    DIRECTION OUTPUT ;
    USE SIGNAL ;
    PORT
      LAYER met4 ;
        RECT 290.370000 566.040000 290.670000 566.840000 ;
    END
  END adc_status[15]
  PIN adc_status[14]
    DIRECTION OUTPUT ;
    USE SIGNAL ;
    PORT
      LAYER met4 ;
        RECT 290.370000 0.000000 290.670000 0.800000 ;
    END
  END adc_status[14]
  PIN adc_status[13]
    DIRECTION OUTPUT ;
    USE SIGNAL ;
    PORT
      LAYER met4 ;
        RECT 285.450000 566.040000 285.750000 566.840000 ;
    END
  END adc_status[13]
  PIN adc_status[12]
    DIRECTION OUTPUT ;
    USE SIGNAL ;
    PORT
      LAYER met4 ;
        RECT 285.450000 0.000000 285.750000 0.800000 ;
    END
  END adc_status[12]
  PIN adc_status[11]
    DIRECTION OUTPUT ;
    USE SIGNAL ;
    PORT
      LAYER met3 ;
        RECT 0.000000 239.950000 0.800000 240.250000 ;
    END
  END adc_status[11]
  PIN adc_status[10]
    DIRECTION OUTPUT ;
    USE SIGNAL ;
    PORT
      LAYER met3 ;
        RECT 0.000000 241.170000 0.800000 241.470000 ;
    END
  END adc_status[10]
  PIN adc_status[9]
    DIRECTION OUTPUT ;
    USE SIGNAL ;
    PORT
      LAYER met3 ;
        RECT 0.000000 242.390000 0.800000 242.690000 ;
    END
  END adc_status[9]
  PIN adc_status[8]
    DIRECTION OUTPUT ;
    USE SIGNAL ;
    PORT
      LAYER met3 ;
        RECT 0.000000 243.610000 0.800000 243.910000 ;
    END
  END adc_status[8]
  PIN adc_status[7]
    DIRECTION OUTPUT ;
    USE SIGNAL ;
    PORT
      LAYER met2 ;
        RECT 285.290000 566.355000 285.430000 566.840000 ;
    END
  END adc_status[7]
  PIN adc_status[6]
    DIRECTION OUTPUT ;
    USE SIGNAL ;
    PORT
      LAYER met2 ;
        RECT 291.050000 566.355000 291.190000 566.840000 ;
    END
  END adc_status[6]
  PIN adc_status[5]
    DIRECTION OUTPUT ;
    USE SIGNAL ;
    PORT
      LAYER met5 ;
        RECT 0.000000 237.470000 2.500000 239.070000 ;
    END
  END adc_status[5]
  PIN adc_status[4]
    DIRECTION OUTPUT ;
    USE SIGNAL ;
    PORT
      LAYER met3 ;
        RECT 0.000000 263.130000 0.800000 263.430000 ;
    END
  END adc_status[4]
  PIN adc_status[3]
    DIRECTION OUTPUT ;
    USE SIGNAL ;
    PORT
      LAYER met2 ;
        RECT 285.290000 0.000000 285.430000 0.485000 ;
    END
  END adc_status[3]
  PIN adc_status[2]
    DIRECTION OUTPUT ;
    USE SIGNAL ;
    PORT
      LAYER met2 ;
        RECT 291.050000 0.000000 291.190000 0.485000 ;
    END
  END adc_status[2]
  PIN adc_status[1]
    DIRECTION OUTPUT ;
    USE SIGNAL ;
    PORT
      LAYER met2 ;
        RECT 172.490000 0.000000 172.630000 0.485000 ;
    END
  END adc_status[1]
  PIN adc_status[0]
    DIRECTION OUTPUT ;
    USE SIGNAL ;
    PORT
      LAYER met3 ;
        RECT 0.000000 152.720000 0.800000 153.020000 ;
    END
  END adc_status[0]
  OBS
    LAYER met1 ;
      RECT 0.000000 0.000000 576.480000 566.840000 ;
    LAYER met2 ;
      RECT 426.210000 566.215000 576.480000 566.840000 ;
      RECT 301.410000 566.215000 425.790000 566.840000 ;
      RECT 299.010000 566.215000 300.990000 566.840000 ;
      RECT 295.170000 566.215000 298.590000 566.840000 ;
      RECT 294.210000 566.215000 294.750000 566.840000 ;
      RECT 293.250000 566.215000 293.790000 566.840000 ;
      RECT 292.290000 566.215000 292.830000 566.840000 ;
      RECT 291.330000 566.215000 291.870000 566.840000 ;
      RECT 290.370000 566.215000 290.910000 566.840000 ;
      RECT 289.410000 566.215000 289.950000 566.840000 ;
      RECT 288.450000 566.215000 288.990000 566.840000 ;
      RECT 287.490000 566.215000 288.030000 566.840000 ;
      RECT 286.530000 566.215000 287.070000 566.840000 ;
      RECT 285.570000 566.215000 286.110000 566.840000 ;
      RECT 284.610000 566.215000 285.150000 566.840000 ;
      RECT 283.650000 566.215000 284.190000 566.840000 ;
      RECT 282.690000 566.215000 283.230000 566.840000 ;
      RECT 281.730000 566.215000 282.270000 566.840000 ;
      RECT 273.090000 566.215000 281.310000 566.840000 ;
      RECT 269.730000 566.215000 272.670000 566.840000 ;
      RECT 268.770000 566.215000 269.310000 566.840000 ;
      RECT 267.330000 566.215000 268.350000 566.840000 ;
      RECT 266.370000 566.215000 266.910000 566.840000 ;
      RECT 263.490000 566.215000 265.950000 566.840000 ;
      RECT 260.130000 566.215000 263.070000 566.840000 ;
      RECT 251.970000 566.215000 259.710000 566.840000 ;
      RECT 248.610000 566.215000 251.550000 566.840000 ;
      RECT 246.210000 566.215000 248.190000 566.840000 ;
      RECT 0.000000 566.215000 245.790000 566.840000 ;
      RECT 0.000000 0.625000 576.480000 566.215000 ;
      RECT 349.890000 0.000000 576.480000 0.625000 ;
      RECT 309.090000 0.000000 349.470000 0.625000 ;
      RECT 306.210000 0.000000 308.670000 0.625000 ;
      RECT 302.850000 0.000000 305.790000 0.625000 ;
      RECT 301.410000 0.000000 302.430000 0.625000 ;
      RECT 299.970000 0.000000 300.990000 0.625000 ;
      RECT 297.570000 0.000000 299.550000 0.625000 ;
      RECT 295.170000 0.000000 297.150000 0.625000 ;
      RECT 294.210000 0.000000 294.750000 0.625000 ;
      RECT 293.250000 0.000000 293.790000 0.625000 ;
      RECT 292.290000 0.000000 292.830000 0.625000 ;
      RECT 291.330000 0.000000 291.870000 0.625000 ;
      RECT 290.370000 0.000000 290.910000 0.625000 ;
      RECT 289.410000 0.000000 289.950000 0.625000 ;
      RECT 288.450000 0.000000 288.990000 0.625000 ;
      RECT 287.490000 0.000000 288.030000 0.625000 ;
      RECT 286.530000 0.000000 287.070000 0.625000 ;
      RECT 285.570000 0.000000 286.110000 0.625000 ;
      RECT 284.610000 0.000000 285.150000 0.625000 ;
      RECT 283.650000 0.000000 284.190000 0.625000 ;
      RECT 282.690000 0.000000 283.230000 0.625000 ;
      RECT 281.730000 0.000000 282.270000 0.625000 ;
      RECT 276.450000 0.000000 281.310000 0.625000 ;
      RECT 274.530000 0.000000 276.030000 0.625000 ;
      RECT 272.130000 0.000000 274.110000 0.625000 ;
      RECT 270.690000 0.000000 271.710000 0.625000 ;
      RECT 267.810000 0.000000 270.270000 0.625000 ;
      RECT 266.370000 0.000000 267.390000 0.625000 ;
      RECT 264.450000 0.000000 265.950000 0.625000 ;
      RECT 263.490000 0.000000 264.030000 0.625000 ;
      RECT 259.650000 0.000000 263.070000 0.625000 ;
      RECT 256.290000 0.000000 259.230000 0.625000 ;
      RECT 253.890000 0.000000 255.870000 0.625000 ;
      RECT 252.930000 0.000000 253.470000 0.625000 ;
      RECT 251.490000 0.000000 252.510000 0.625000 ;
      RECT 250.530000 0.000000 251.070000 0.625000 ;
      RECT 249.570000 0.000000 250.110000 0.625000 ;
      RECT 248.610000 0.000000 249.150000 0.625000 ;
      RECT 247.650000 0.000000 248.190000 0.625000 ;
      RECT 246.210000 0.000000 247.230000 0.625000 ;
      RECT 245.250000 0.000000 245.790000 0.625000 ;
      RECT 244.290000 0.000000 244.830000 0.625000 ;
      RECT 242.850000 0.000000 243.870000 0.625000 ;
      RECT 237.570000 0.000000 242.430000 0.625000 ;
      RECT 234.210000 0.000000 237.150000 0.625000 ;
      RECT 230.370000 0.000000 233.790000 0.625000 ;
      RECT 228.930000 0.000000 229.950000 0.625000 ;
      RECT 222.690000 0.000000 228.510000 0.625000 ;
      RECT 221.730000 0.000000 222.270000 0.625000 ;
      RECT 215.010000 0.000000 221.310000 0.625000 ;
      RECT 211.170000 0.000000 214.590000 0.625000 ;
      RECT 209.730000 0.000000 210.750000 0.625000 ;
      RECT 203.970000 0.000000 209.310000 0.625000 ;
      RECT 195.810000 0.000000 203.550000 0.625000 ;
      RECT 190.530000 0.000000 195.390000 0.625000 ;
      RECT 189.570000 0.000000 190.110000 0.625000 ;
      RECT 184.770000 0.000000 189.150000 0.625000 ;
      RECT 183.810000 0.000000 184.350000 0.625000 ;
      RECT 182.850000 0.000000 183.390000 0.625000 ;
      RECT 179.970000 0.000000 182.430000 0.625000 ;
      RECT 177.090000 0.000000 179.550000 0.625000 ;
      RECT 174.690000 0.000000 176.670000 0.625000 ;
      RECT 172.770000 0.000000 174.270000 0.625000 ;
      RECT 154.050000 0.000000 172.350000 0.625000 ;
      RECT 152.130000 0.000000 153.630000 0.625000 ;
      RECT 149.730000 0.000000 151.710000 0.625000 ;
      RECT 148.770000 0.000000 149.310000 0.625000 ;
      RECT 143.970000 0.000000 148.350000 0.625000 ;
      RECT 139.650000 0.000000 143.550000 0.625000 ;
      RECT 136.770000 0.000000 139.230000 0.625000 ;
      RECT 0.000000 0.000000 136.350000 0.625000 ;
    LAYER met3 ;
      RECT 0.000000 490.040000 576.480000 566.840000 ;
      RECT 1.100000 489.140000 576.480000 490.040000 ;
      RECT 0.000000 308.870000 576.480000 489.140000 ;
      RECT 1.100000 307.970000 576.480000 308.870000 ;
      RECT 0.000000 307.650000 576.480000 307.970000 ;
      RECT 1.100000 306.750000 576.480000 307.650000 ;
      RECT 0.000000 305.820000 576.480000 306.750000 ;
      RECT 1.100000 304.920000 576.480000 305.820000 ;
      RECT 0.000000 302.160000 576.480000 304.920000 ;
      RECT 1.100000 301.260000 576.480000 302.160000 ;
      RECT 0.000000 300.940000 576.480000 301.260000 ;
      RECT 1.100000 300.040000 576.480000 300.940000 ;
      RECT 0.000000 297.280000 576.480000 300.040000 ;
      RECT 1.100000 296.380000 576.480000 297.280000 ;
      RECT 0.000000 293.620000 576.480000 296.380000 ;
      RECT 1.100000 292.720000 576.480000 293.620000 ;
      RECT 0.000000 292.400000 576.480000 292.720000 ;
      RECT 1.100000 291.500000 576.480000 292.400000 ;
      RECT 0.000000 291.180000 576.480000 291.500000 ;
      RECT 1.100000 290.280000 576.480000 291.180000 ;
      RECT 0.000000 289.960000 576.480000 290.280000 ;
      RECT 1.100000 289.060000 576.480000 289.960000 ;
      RECT 0.000000 288.740000 576.480000 289.060000 ;
      RECT 1.100000 288.130000 576.480000 288.740000 ;
      RECT 1.100000 287.840000 575.380000 288.130000 ;
      RECT 0.000000 287.230000 575.380000 287.840000 ;
      RECT 0.000000 286.910000 576.480000 287.230000 ;
      RECT 0.000000 286.010000 575.380000 286.910000 ;
      RECT 0.000000 285.080000 576.480000 286.010000 ;
      RECT 1.100000 284.180000 575.380000 285.080000 ;
      RECT 0.000000 283.860000 576.480000 284.180000 ;
      RECT 1.100000 282.960000 575.380000 283.860000 ;
      RECT 0.000000 282.640000 576.480000 282.960000 ;
      RECT 1.100000 281.740000 575.380000 282.640000 ;
      RECT 0.000000 281.420000 576.480000 281.740000 ;
      RECT 1.100000 280.520000 576.480000 281.420000 ;
      RECT 0.000000 280.200000 576.480000 280.520000 ;
      RECT 1.100000 279.300000 575.380000 280.200000 ;
      RECT 0.000000 276.540000 576.480000 279.300000 ;
      RECT 1.100000 275.640000 576.480000 276.540000 ;
      RECT 0.000000 271.050000 576.480000 275.640000 ;
      RECT 1.100000 270.150000 575.380000 271.050000 ;
      RECT 0.000000 268.610000 576.480000 270.150000 ;
      RECT 1.100000 267.710000 576.480000 268.610000 ;
      RECT 0.000000 267.390000 576.480000 267.710000 ;
      RECT 1.100000 266.490000 576.480000 267.390000 ;
      RECT 0.000000 266.170000 576.480000 266.490000 ;
      RECT 1.100000 265.270000 576.480000 266.170000 ;
      RECT 0.000000 264.950000 576.480000 265.270000 ;
      RECT 1.100000 264.050000 576.480000 264.950000 ;
      RECT 0.000000 263.730000 576.480000 264.050000 ;
      RECT 1.100000 262.830000 576.480000 263.730000 ;
      RECT 0.000000 259.460000 576.480000 262.830000 ;
      RECT 1.100000 258.560000 576.480000 259.460000 ;
      RECT 0.000000 250.920000 576.480000 258.560000 ;
      RECT 1.100000 250.020000 576.480000 250.920000 ;
      RECT 0.000000 249.700000 576.480000 250.020000 ;
      RECT 1.100000 248.800000 576.480000 249.700000 ;
      RECT 0.000000 248.480000 576.480000 248.800000 ;
      RECT 1.100000 247.580000 576.480000 248.480000 ;
      RECT 0.000000 246.650000 576.480000 247.580000 ;
      RECT 1.100000 245.750000 576.480000 246.650000 ;
      RECT 0.000000 245.430000 576.480000 245.750000 ;
      RECT 1.100000 244.530000 576.480000 245.430000 ;
      RECT 0.000000 244.210000 576.480000 244.530000 ;
      RECT 1.100000 243.310000 576.480000 244.210000 ;
      RECT 0.000000 242.990000 576.480000 243.310000 ;
      RECT 1.100000 242.090000 576.480000 242.990000 ;
      RECT 0.000000 241.770000 576.480000 242.090000 ;
      RECT 1.100000 240.870000 576.480000 241.770000 ;
      RECT 0.000000 240.550000 576.480000 240.870000 ;
      RECT 1.100000 239.650000 576.480000 240.550000 ;
      RECT 0.000000 239.330000 576.480000 239.650000 ;
      RECT 1.100000 238.430000 576.480000 239.330000 ;
      RECT 0.000000 238.110000 576.480000 238.430000 ;
      RECT 1.100000 237.210000 576.480000 238.110000 ;
      RECT 0.000000 236.890000 576.480000 237.210000 ;
      RECT 1.100000 235.990000 576.480000 236.890000 ;
      RECT 0.000000 235.670000 576.480000 235.990000 ;
      RECT 1.100000 235.060000 576.480000 235.670000 ;
      RECT 1.100000 234.770000 575.380000 235.060000 ;
      RECT 0.000000 234.450000 575.380000 234.770000 ;
      RECT 1.100000 234.160000 575.380000 234.450000 ;
      RECT 1.100000 233.550000 576.480000 234.160000 ;
      RECT 0.000000 233.230000 576.480000 233.550000 ;
      RECT 1.100000 232.330000 575.380000 233.230000 ;
      RECT 0.000000 228.350000 576.480000 232.330000 ;
      RECT 1.100000 227.450000 576.480000 228.350000 ;
      RECT 0.000000 224.690000 576.480000 227.450000 ;
      RECT 1.100000 223.790000 576.480000 224.690000 ;
      RECT 0.000000 212.490000 576.480000 223.790000 ;
      RECT 1.100000 211.590000 576.480000 212.490000 ;
      RECT 0.000000 210.660000 576.480000 211.590000 ;
      RECT 1.100000 209.760000 576.480000 210.660000 ;
      RECT 0.000000 197.240000 576.480000 209.760000 ;
      RECT 1.100000 196.340000 576.480000 197.240000 ;
      RECT 0.000000 196.020000 576.480000 196.340000 ;
      RECT 1.100000 195.120000 576.480000 196.020000 ;
      RECT 0.000000 187.480000 576.480000 195.120000 ;
      RECT 1.100000 186.580000 576.480000 187.480000 ;
      RECT 0.000000 172.840000 576.480000 186.580000 ;
      RECT 1.100000 171.940000 576.480000 172.840000 ;
      RECT 0.000000 170.400000 576.480000 171.940000 ;
      RECT 1.100000 169.500000 576.480000 170.400000 ;
      RECT 0.000000 169.180000 576.480000 169.500000 ;
      RECT 1.100000 168.280000 576.480000 169.180000 ;
      RECT 0.000000 167.960000 576.480000 168.280000 ;
      RECT 1.100000 167.060000 576.480000 167.960000 ;
      RECT 0.000000 166.740000 576.480000 167.060000 ;
      RECT 1.100000 165.840000 576.480000 166.740000 ;
      RECT 0.000000 164.300000 576.480000 165.840000 ;
      RECT 1.100000 163.400000 576.480000 164.300000 ;
      RECT 0.000000 159.420000 576.480000 163.400000 ;
      RECT 1.100000 158.520000 576.480000 159.420000 ;
      RECT 0.000000 153.320000 576.480000 158.520000 ;
      RECT 1.100000 152.420000 576.480000 153.320000 ;
      RECT 0.000000 97.810000 576.480000 152.420000 ;
      RECT 0.000000 96.910000 575.380000 97.810000 ;
      RECT 0.000000 0.000000 576.480000 96.910000 ;
    LAYER met4 ;
      RECT 298.965000 565.740000 576.480000 566.840000 ;
      RECT 295.890000 565.740000 298.065000 566.840000 ;
      RECT 294.660000 565.740000 294.990000 566.840000 ;
      RECT 293.430000 565.740000 293.760000 566.840000 ;
      RECT 292.200000 565.740000 292.530000 566.840000 ;
      RECT 290.970000 565.740000 291.300000 566.840000 ;
      RECT 289.740000 565.740000 290.070000 566.840000 ;
      RECT 288.510000 565.740000 288.840000 566.840000 ;
      RECT 287.280000 565.740000 287.610000 566.840000 ;
      RECT 286.050000 565.740000 286.380000 566.840000 ;
      RECT 284.820000 565.740000 285.150000 566.840000 ;
      RECT 283.590000 565.740000 283.920000 566.840000 ;
      RECT 282.360000 565.740000 282.690000 566.840000 ;
      RECT 0.000000 565.740000 281.460000 566.840000 ;
      RECT 0.000000 1.100000 576.480000 565.740000 ;
      RECT 294.660000 0.000000 576.480000 1.100000 ;
      RECT 293.430000 0.000000 293.760000 1.100000 ;
      RECT 292.200000 0.000000 292.530000 1.100000 ;
      RECT 290.970000 0.000000 291.300000 1.100000 ;
      RECT 289.740000 0.000000 290.070000 1.100000 ;
      RECT 288.510000 0.000000 288.840000 1.100000 ;
      RECT 287.280000 0.000000 287.610000 1.100000 ;
      RECT 286.050000 0.000000 286.380000 1.100000 ;
      RECT 284.820000 0.000000 285.150000 1.100000 ;
      RECT 283.590000 0.000000 283.920000 1.100000 ;
      RECT 282.360000 0.000000 282.690000 1.100000 ;
      RECT 276.210000 0.000000 281.460000 1.100000 ;
      RECT 265.140000 0.000000 275.310000 1.100000 ;
      RECT 259.605000 0.000000 264.240000 1.100000 ;
      RECT 253.455000 0.000000 258.705000 1.100000 ;
      RECT 250.380000 0.000000 252.555000 1.100000 ;
      RECT 249.150000 0.000000 249.480000 1.100000 ;
      RECT 247.920000 0.000000 248.250000 1.100000 ;
      RECT 246.690000 0.000000 247.020000 1.100000 ;
      RECT 244.230000 0.000000 245.790000 1.100000 ;
      RECT 243.000000 0.000000 243.330000 1.100000 ;
      RECT 233.775000 0.000000 242.100000 1.100000 ;
      RECT 215.940000 0.000000 232.875000 1.100000 ;
      RECT 214.710000 0.000000 215.040000 1.100000 ;
      RECT 184.575000 0.000000 213.810000 1.100000 ;
      RECT 179.655000 0.000000 183.675000 1.100000 ;
      RECT 149.520000 0.000000 178.755000 1.100000 ;
      RECT 148.290000 0.000000 148.620000 1.100000 ;
      RECT 140.295000 0.000000 147.390000 1.100000 ;
      RECT 0.000000 0.000000 139.395000 1.100000 ;
    LAYER met5 ;
      RECT 0.000000 310.210000 576.480000 566.840000 ;
      RECT 4.100000 305.410000 576.480000 310.210000 ;
      RECT 0.000000 302.890000 576.480000 305.410000 ;
      RECT 4.100000 298.090000 576.480000 302.890000 ;
      RECT 0.000000 291.910000 576.480000 298.090000 ;
      RECT 4.100000 287.110000 576.480000 291.910000 ;
      RECT 0.000000 284.590000 576.480000 287.110000 ;
      RECT 4.100000 279.790000 572.380000 284.590000 ;
      RECT 0.000000 273.610000 576.480000 279.790000 ;
      RECT 4.100000 268.810000 576.480000 273.610000 ;
      RECT 0.000000 266.290000 576.480000 268.810000 ;
      RECT 4.100000 261.490000 576.480000 266.290000 ;
      RECT 0.000000 247.990000 576.480000 261.490000 ;
      RECT 4.100000 243.190000 576.480000 247.990000 ;
      RECT 0.000000 240.670000 576.480000 243.190000 ;
      RECT 4.100000 235.870000 576.480000 240.670000 ;
      RECT 0.000000 215.050000 576.480000 235.870000 ;
      RECT 4.100000 210.250000 576.480000 215.050000 ;
      RECT 0.000000 171.130000 576.480000 210.250000 ;
      RECT 4.100000 166.330000 576.480000 171.130000 ;
      RECT 0.000000 0.000000 576.480000 166.330000 ;
  END
END adc_subsystem_macro

END LIBRARY
